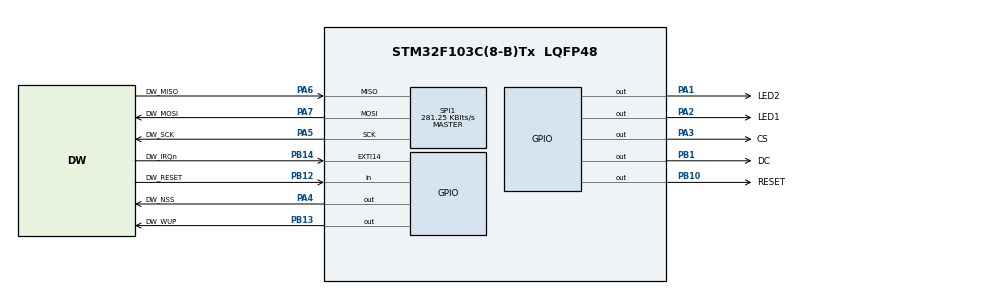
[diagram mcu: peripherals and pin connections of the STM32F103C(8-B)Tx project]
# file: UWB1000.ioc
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Mcu.Family=STM32F1
Mcu.Name=STM32F103C(8-B)Tx
Mcu.Package=LQFP48
NVIC.PriorityGroup=NVIC_PRIORITYGROUP_4
PA1.GPIO_Label=LED2
PA1.Signal=GPIO_Output
PA13.Mode=Serial_Wire
PA13.Signal=SYS_JTMS-SWDIO
PA14.Mode=Serial_Wire
PA14.Signal=SYS_JTCK-SWCLK
PA2.GPIO_Label=LED1
PA2.Signal=GPIO_Output
PA3.GPIO_Label=CS
PA3.Signal=GPIO_Output
PA4.GPIO_Label=DW_NSS
PA4.Signal=GPIO_Output
PA5.GPIO_Label=DW_SCK
PA5.Mode=Full_Duplex_Master
PA5.Signal=SPI1_SCK
PA6.GPIO_Label=DW_MISO
PA6.Mode=Full_Duplex_Master
PA6.Signal=SPI1_MISO
PA7.GPIO_Label=DW_MOSI
PA7.Mode=Full_Duplex_Master
PA7.Signal=SPI1_MOSI
PB1.GPIO_Label=DC
PB1.Signal=GPIO_Output
PB10.GPIO_Label=RESET
PB10.Signal=GPIO_Output
PB12.GPIO_Label=DW_RESET
PB12.Signal=GPIO_Input
PB13.GPIO_Label=DW_WUP
PB13.Signal=GPIO_Output
PB14.GPIO_Label=DW_IRQn
PB14.Signal=GPXTI14
PD0-OSC_IN.Mode=HSE-External-Oscillator
PD0-OSC_IN.Signal=RCC_OSC_IN
PD1-OSC_OUT.Mode=HSE-External-Oscillator
PD1-OSC_OUT.Signal=RCC_OSC_OUT
ProjectManager.HeapSize=0x200
ProjectManager.StackSize=0x400
ProjectManager.TargetToolchain=STM32CubeIDE
RCC.AHBFreq_Value=72000000
RCC.APB1CLKDivider=RCC_HCLK_DIV2
RCC.APB1Freq_Value=36000000
RCC.APB1TimFreq_Value=72000000
RCC.APB2Freq_Value=72000000
RCC.APB2TimFreq_Value=72000000
RCC.HCLKFreq_Value=72000000
RCC.PLLMUL=RCC_PLL_MUL9
RCC.PLLSourceVirtual=RCC_PLLSOURCE_HSE
RCC.SYSCLKFreq_VALUE=72000000
RCC.SYSCLKSource=RCC_SYSCLKSOURCE_PLLCLK
RCC.USBFreq_Value=72000000
SPI1.BaudRatePrescaler=SPI_BAUDRATEPRESCALER_256
SPI1.CalculateBaudRate=281.25 KBits/s
SPI1.Direction=SPI_DIRECTION_2LINES
SPI1.Mode=SPI_MODE_MASTER
SPI1.VirtualType=VM_MASTER
board=custom

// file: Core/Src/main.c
/* USER CODE BEGIN Header */
/**
  ******************************************************************************
  * @file           : main.c
  * @brief          : Main program body
  ******************************************************************************
  * @attention
  *
  * Copyright (c) 2021 STMicroelectronics.
  * All rights reserved.
  *
  * This software is licensed under terms that can be found in the LICENSE file
  * in the root directory of this software component.
  * If no LICENSE file comes with this software, it is provided AS-IS.
  *
  ******************************************************************************
  */
/* USER CODE END Header */
#include "main.h"
/* USER CODE BEGIN Includes */
#include<stdio.h>
#include <ILI9341_Driver.h>
#include "port.h"

#define EX_01A_DEF
// #define EX_02A_DEF

#ifdef EX_01A_DEF
#include <./ex_01a_simple_tx/ex_01a_main.c>
#endif
#ifdef EX_02A_DEF
#include "./ex_02a_simple_rx/ex_02a_main.c"
#endif

/* USER CODE END Includes */

SPI_HandleTypeDef hspi1;

void SystemClock_Config(void);
static void MX_GPIO_Init(void);
static void MX_SPI1_Init(void);

int main(void)
{

  /* MCU Configuration--------------------------------------------------------*/

  /* Reset of all peripherals, Initializes the Flash interface and the Systick. */
  HAL_Init();

  /* Configure the system clock */
  SystemClock_Config();

  /* Initialize all configured peripherals */
  MX_GPIO_Init();
  MX_SPI1_Init();
  /* USER CODE BEGIN 2 */

  ILI9341_Init();
  ILI9341_Set_Rotation(3);
  ILI9341_Fill_Screen(BLACK);
  ILI9341_Draw_String(20, 20, RED, BLACK, "****** Debug Logs ******", 2);
  ILI9341_Draw_String(20, 60, GREENYELLOW, BLACK, ">>$", 2);

  setup_DW1000RSTnIRQ(1);
  dw_main();
  /* USER CODE END 2 */

  /* Infinite loop */
  while (1)
  {

  }
}

void SystemClock_Config(void)
{
  RCC_OscInitTypeDef RCC_OscInitStruct = {0};
  RCC_ClkInitTypeDef RCC_ClkInitStruct = {0};

  /** Initializes the RCC Oscillators according to the specified parameters
  * in the RCC_OscInitTypeDef structure.
  */
  RCC_OscInitStruct.OscillatorType = RCC_OSCILLATORTYPE_HSE;
  RCC_OscInitStruct.HSEState = RCC_HSE_ON;
  RCC_OscInitStruct.HSEPredivValue = RCC_HSE_PREDIV_DIV1;
  RCC_OscInitStruct.HSIState = RCC_HSI_ON;
  RCC_OscInitStruct.PLL.PLLState = RCC_PLL_ON;
  RCC_OscInitStruct.PLL.PLLSource = RCC_PLLSOURCE_HSE;
  RCC_OscInitStruct.PLL.PLLMUL = RCC_PLL_MUL5;
  if (HAL_RCC_OscConfig(&RCC_OscInitStruct) != HAL_OK)
  {
    Error_Handler();
  }
  /** Initializes the CPU, AHB and APB buses clocks
  */
  RCC_ClkInitStruct.ClockType = RCC_CLOCKTYPE_HCLK|RCC_CLOCKTYPE_SYSCLK
                              |RCC_CLOCKTYPE_PCLK1|RCC_CLOCKTYPE_PCLK2;
  RCC_ClkInitStruct.SYSCLKSource = RCC_SYSCLKSOURCE_PLLCLK;
  RCC_ClkInitStruct.AHBCLKDivider = RCC_SYSCLK_DIV1;
  RCC_ClkInitStruct.APB1CLKDivider = RCC_HCLK_DIV2;
  RCC_ClkInitStruct.APB2CLKDivider = RCC_HCLK_DIV1;

  if (HAL_RCC_ClockConfig(&RCC_ClkInitStruct, FLASH_LATENCY_1) != HAL_OK)
  {
    Error_Handler();
  }
}

static void MX_SPI1_Init(void)
{

  /* SPI1 parameter configuration*/
  hspi1.Instance = SPI1;
  hspi1.Init.Mode = SPI_MODE_MASTER;
  hspi1.Init.Direction = SPI_DIRECTION_2LINES;
  hspi1.Init.DataSize = SPI_DATASIZE_8BIT;
  hspi1.Init.CLKPolarity = SPI_POLARITY_LOW;
  hspi1.Init.CLKPhase = SPI_PHASE_1EDGE;
  hspi1.Init.NSS = SPI_NSS_SOFT;
  hspi1.Init.BaudRatePrescaler = SPI_BAUDRATEPRESCALER_256;
  hspi1.Init.FirstBit = SPI_FIRSTBIT_MSB;
  hspi1.Init.TIMode = SPI_TIMODE_DISABLE;
  hspi1.Init.CRCCalculation = SPI_CRCCALCULATION_DISABLE;
  hspi1.Init.CRCPolynomial = 10;
  if (HAL_SPI_Init(&hspi1) != HAL_OK)
  {
    Error_Handler();
  }

}

static void MX_GPIO_Init(void)
{
  GPIO_InitTypeDef GPIO_InitStruct = {0};

  /* GPIO Ports Clock Enable */
  __HAL_RCC_GPIOD_CLK_ENABLE();
  __HAL_RCC_GPIOA_CLK_ENABLE();
  __HAL_RCC_GPIOB_CLK_ENABLE();

  /*Configure GPIO pin Output Level */
  HAL_GPIO_WritePin(GPIOA, LED2_Pin|LED1_Pin|CS_Pin|DW_NSS_Pin, GPIO_PIN_RESET);

  /*Configure GPIO pin Output Level */
  HAL_GPIO_WritePin(GPIOB, DC_Pin|RESET_Pin|DW_WUP_Pin, GPIO_PIN_RESET);

  /*Configure GPIO pins : LED2_Pin LED1_Pin CS_Pin DW_NSS_Pin */
  GPIO_InitStruct.Pin = LED2_Pin|LED1_Pin|CS_Pin|DW_NSS_Pin;
  GPIO_InitStruct.Mode = GPIO_MODE_OUTPUT_PP;
  GPIO_InitStruct.Pull = GPIO_NOPULL;
  GPIO_InitStruct.Speed = GPIO_SPEED_FREQ_LOW;
  HAL_GPIO_Init(GPIOA, &GPIO_InitStruct);

  /*Configure GPIO pins : DC_Pin RESET_Pin DW_WUP_Pin */
  GPIO_InitStruct.Pin = DC_Pin|RESET_Pin|DW_WUP_Pin;
  GPIO_InitStruct.Mode = GPIO_MODE_OUTPUT_PP;
  GPIO_InitStruct.Pull = GPIO_NOPULL;
  GPIO_InitStruct.Speed = GPIO_SPEED_FREQ_LOW;
  HAL_GPIO_Init(GPIOB, &GPIO_InitStruct);

  /*Configure GPIO pin : DW_RESET_Pin */
  GPIO_InitStruct.Pin = DW_RESET_Pin;
  GPIO_InitStruct.Mode = GPIO_MODE_INPUT;
  GPIO_InitStruct.Pull = GPIO_NOPULL;
  HAL_GPIO_Init(DW_RESET_GPIO_Port, &GPIO_InitStruct);

  /*Configure GPIO pin : DW_IRQn_Pin */
  GPIO_InitStruct.Pin = DW_IRQn_Pin;
  GPIO_InitStruct.Mode = GPIO_MODE_IT_RISING;
  GPIO_InitStruct.Pull = GPIO_NOPULL;
  HAL_GPIO_Init(DW_IRQn_GPIO_Port, &GPIO_InitStruct);

}

void Error_Handler(void)
{
  __disable_irq();
  while (1)
  {
  }
}
